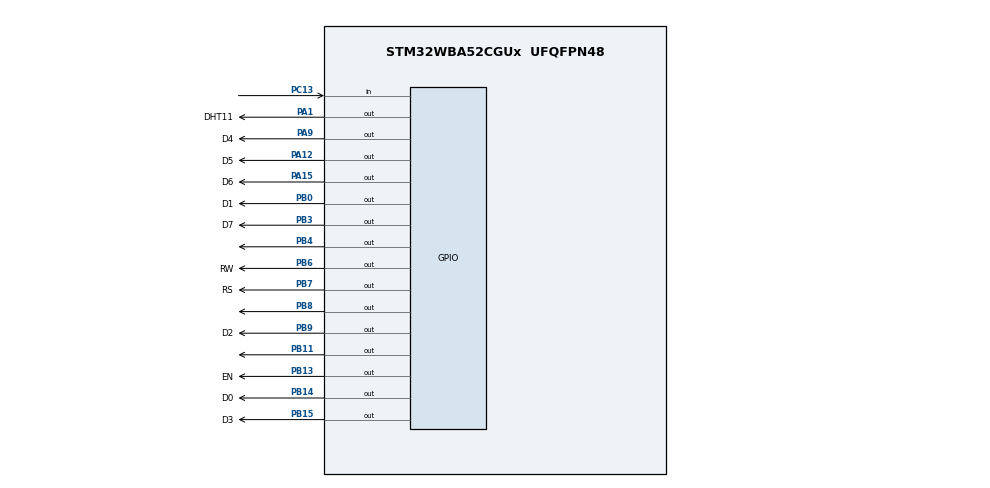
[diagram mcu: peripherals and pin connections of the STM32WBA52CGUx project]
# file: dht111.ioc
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CORTEX_M33_NS.userName=CORTEX_M33
Mcu.Family=STM32WBA
Mcu.Name=STM32WBA52CGUx
Mcu.Package=UFQFPN48
NUCLEO-WBA52CG.BUTTON=1
NUCLEO-WBA52CG.BUTTON2=1
NUCLEO-WBA52CG.BUTTON3=1
NUCLEO-WBA52CG.LD1=true
NUCLEO-WBA52CG.LD2=true
NUCLEO-WBA52CG.LD3=true
NUCLEO-WBA52CG.VCP=true
NVIC.EXTI13_IRQn=true\:0\:0\:false\:false\:true\:true\:true\:true
NVIC.EXTI6_IRQn=true\:0\:0\:false\:false\:true\:true\:true\:true
NVIC.EXTI7_IRQn=true\:0\:0\:false\:false\:true\:true\:true\:true
NVIC.PriorityGroup=NVIC_PRIORITYGROUP_4
OSC_IN.GPIO_Label=RCC_OSC_IN
OSC_IN.Mode=HSE-External-Oscillator
OSC_IN.Signal=RCC_OSC_IN
OSC_OUT.GPIO_Label=RCC_OSC_OUT
OSC_OUT.Mode=HSE-External-Oscillator
OSC_OUT.Signal=RCC_OSC_OUT
PA1.GPIO_Label=DHT11
PA1.Signal=GPIO_Output
PA12.GPIO_Label=D5
PA12.Signal=GPIO_Output
PA13\ (JTMS/SWDIO).GPIO_Label=DEBUG_JTMS-SWDIO
PA13\ (JTMS/SWDIO).Signal=DEBUG_JTMS-SWDIO
PA14\ (JTCK/SWCLK).GPIO_Label=DEBUG_JTCK-SWCLK
PA14\ (JTCK/SWCLK).Signal=DEBUG_JTCK-SWCLK
PA15\ (JTDI).GPIO_Label=D6
PA15\ (JTDI).Signal=GPIO_Output
PA8.Signal=USART1_RX
PA9.GPIO_Label=D4
PA9.Signal=GPIO_Output
PB0.GPIO_Label=D1
PB0.Signal=GPIO_Output
PB11.Signal=GPIO_Output
PB12.Signal=USART1_TX
PB13.GPIO_Label=EN
PB13.Signal=GPIO_Output
PB14.GPIO_Label=D0
PB14.Signal=GPIO_Output
PB15.GPIO_Label=D3
PB15.Signal=GPIO_Output
PB3\ (JTDO/TRACESWO).GPIO_Label=D7
PB3\ (JTDO/TRACESWO).Signal=GPIO_Output
PB4\ (NJTRST).Signal=GPIO_Output
PB6.GPIO_Label=RW
PB6.Signal=GPIO_Output
PB7.GPIO_Label=RS
PB7.Signal=GPIO_Output
PB8.Signal=GPIO_Output
PB9.GPIO_Label=D2
PB9.Signal=GPIO_Output
PC13.Signal=GPIO_Input
PC14-OSC32_IN.GPIO_Label=RCC_OSC32_IN
PC14-OSC32_IN.Signal=RCC_OSC32_IN
PC15-OSC32_OUT.GPIO_Label=RCC_OSC32_OUT
PC15-OSC32_OUT.Signal=RCC_OSC32_OUT
ProjectManager.HeapSize=0x200
ProjectManager.StackSize=0x400
ProjectManager.TargetToolchain=STM32CubeIDE
RCC.ADCFreq_Value=50000000
RCC.AHB5CLKDivider=DIV2
RCC.AHBFreq_Value=50000000
RCC.APB1Freq_Value=50000000
RCC.APB1TimFreq_Value=50000000
RCC.APB2Freq_Value=50000000
RCC.APB2TimFreq_Value=50000000
RCC.CortexFreq_Value=6250000
RCC.FLatency=FLASH_LATENCY_1
RCC.HCLKFreq_Value=50000000
RCC.HSE_VALUE=32000000
RCC.HSI_VALUE=16000000
RCC.LSE_VALUE=32768
RCC.PLL1R=3
RCC.PLLFRACN=3072
RCC.PLLM=2
RCC.PLLN=9
RCC.PLLSourceVirtual=RCC_PLLSOURCE_HSE
RCC.SYSCLKFreq_VALUE=50000000
RCC.SYSCLKSourceVirtual=RCC_SYSCLKSOURCE_PLLCLK
RCC.VCOOutputFreq_Value=150000000
TIM1.Prescaler=50-1
VP_CORTEX_M33_NS_VS_Hclk.Mode=Hclk_Mode
VP_ICACHE_VS_ICACHE.Mode=DirectMappedCache
VP_MEMORYMAP_VS_MEMORYMAP.Mode=CurAppReg
VP_NUCLEO-WBA52CG_VS_BSP_COMMON.Mode=COMMON
VP_PWR_VS_SECSignals.Mode=Security/Privilege
VP_TIM1_VS_ClockSourceINT.Mode=Internal
board=NUCLEO-WBA52CG

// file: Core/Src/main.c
/* USER CODE BEGIN Header */
/* USER CODE END Header */
#include "main.h"
#include"LCD.h"

COM_InitTypeDef BspCOMInit;

TIM_HandleTypeDef htim1;

void SystemClock_Config(void);
static void MX_GPIO_Init(void);
static void MX_ICACHE_Init(void);
static void MX_TIM1_Init(void);

/* USER CODE BEGIN 0 */
void delay (uint16_t time)
{
	/* change your code here for the delay in microseconds */
	__HAL_TIM_SET_COUNTER(&htim1, 0);
	while ((__HAL_TIM_GET_COUNTER(&htim1))<time);
}

void Display_Temp (float Temp)
{
	char str[20] = {0};
	LCD_cmd(0x80);

	sprintf (str, "TEMP:- %.2f ", Temp);
	LCD_Print(str);
	LCD_data('C');
}

void Display_Rh (float Rh)
{
	char str[20] = {0};
	LCD_cmd(0xc0);
	sprintf (str, "RH:- %.2f ", Rh);
	LCD_Print(str);
	LCD_data('H');
}

uint8_t Rh_byte1, Rh_byte2, Temp_byte1, Temp_byte2;
uint16_t SUM, RH, TEMP;

float Temperature = 0;
float Humidity = 0;
uint8_t Presence = 0;

void Set_Pin_Output (GPIO_TypeDef *GPIOx, uint16_t GPIO_Pin)
{
	GPIO_InitTypeDef GPIO_InitStruct = {0};
	GPIO_InitStruct.Pin = GPIO_Pin;
	GPIO_InitStruct.Mode = GPIO_MODE_OUTPUT_PP;
	GPIO_InitStruct.Speed = GPIO_SPEED_FREQ_LOW;
	HAL_GPIO_Init(GPIOx, &GPIO_InitStruct);
}

void Set_Pin_Input (GPIO_TypeDef *GPIOx, uint16_t GPIO_Pin)
{
	GPIO_InitTypeDef GPIO_InitStruct = {0};
	GPIO_InitStruct.Pin = GPIO_Pin;
	GPIO_InitStruct.Mode = GPIO_MODE_INPUT;
	GPIO_InitStruct.Pull = GPIO_PULLUP;
	HAL_GPIO_Init(GPIOx, &GPIO_InitStruct);
}

/*********************************** DHT11 FUNCTIONS ********************************************/

#define DHT11_PORT GPIOA
#define DHT11_PIN GPIO_PIN_1

void DHT11_Start (void)
{
	Set_Pin_Output (DHT11_PORT, DHT11_PIN);  // set the pin as output
	HAL_GPIO_WritePin (DHT11_PORT, DHT11_PIN, 0);   // pull the pin low
	delay (18000);   // wait for 18ms
    HAL_GPIO_WritePin (DHT11_PORT, DHT11_PIN, 1);   // pull the pin high
	delay (20);   // wait for 20us
	Set_Pin_Input(DHT11_PORT, DHT11_PIN);    // set as input
}

uint8_t DHT11_Check_Response (void)
{
	uint8_t Response = 0;
	delay (40);
	if (!(HAL_GPIO_ReadPin (DHT11_PORT, DHT11_PIN)))
	{
		delay (80);
		if ((HAL_GPIO_ReadPin (DHT11_PORT, DHT11_PIN))) Response = 1;
		else Response = -1; // 255
	}
	while ((HAL_GPIO_ReadPin (DHT11_PORT, DHT11_PIN)));   // wait for the pin to go low

	return Response;
}

uint8_t DHT11_Read (void)
{
	uint8_t i,j;
	for (j=0;j<8;j++)
	{
		while (!(HAL_GPIO_ReadPin (DHT11_PORT, DHT11_PIN)));   // wait for the pin to go high
		delay (40);   // wait for 40 us
		if (!(HAL_GPIO_ReadPin (DHT11_PORT, DHT11_PIN)))   // if the pin is low
		{
			i&= ~(1<<(7-j));   // write 0
		}
		else i|= (1<<(7-j));  // if the pin is high, write 1
		while ((HAL_GPIO_ReadPin (DHT11_PORT, DHT11_PIN)));  // wait for the pin to go low
	}
	return i;
}
/* USER CODE END 0 */

int main(void)
{

  /* MCU Configuration--------------------------------------------------------*/

  /* Reset of all peripherals, Initializes the Flash interface and the Systick. */
  HAL_Init();

  /* Configure the system clock */
  SystemClock_Config();

  /* Initialize all configured peripherals */
  MX_GPIO_Init();
  MX_ICACHE_Init();
  MX_TIM1_Init();
  LCD_init();
  /* USER CODE BEGIN 2 */
    LCD_Print("INITIALISING>>>>");
    HAL_Delay(2000);
    LCD_cmd(0x01);

    /* USER CODE END 2 */

    /* Infinite loop */
     while (1)
     {

       /* USER CODE BEGIN 3 */

   	  Display_Temp(Temperature);
   	  Display_Rh(Humidity);

   	  DHT11_Start();
   	  Presence = DHT11_Check_Response();
   	  Rh_byte1 = DHT11_Read ();
   	  Rh_byte2 = DHT11_Read ();
   	  Temp_byte1 = DHT11_Read ();
   	  Temp_byte2 = DHT11_Read ();
   	  SUM = DHT11_Read();

   	  TEMP = Temp_byte1;
   	  RH = Rh_byte1;

   	  Temperature = (float) TEMP;
   	  Humidity = (float) RH;

   	  HAL_Delay(1000);

     }

  /* USER CODE END 2 */
  /* Initialize COM1 port (115200, 8 bits (7-bit data + 1 stop bit), no parity */
  BspCOMInit.BaudRate   = 115200;
  BspCOMInit.WordLength = COM_WORDLENGTH_8B;
  BspCOMInit.StopBits   = COM_STOPBITS_1;
  BspCOMInit.Parity     = COM_PARITY_NONE;
  BspCOMInit.HwFlowCtl  = COM_HWCONTROL_NONE;
  if (BSP_COM_Init(COM1, &BspCOMInit) != BSP_ERROR_NONE)
  {
    Error_Handler();
  }

  /* Infinite loop */
  /* USER CODE BEGIN WHILE */
    /* USER CODE END WHILE */

    /* USER CODE BEGIN 3 */
  /* USER CODE END 3 */
}

void SystemClock_Config(void)
{
  RCC_OscInitTypeDef RCC_OscInitStruct = {0};
  RCC_ClkInitTypeDef RCC_ClkInitStruct = {0};

  /** Configure the main internal regulator output voltage
  */
  if (HAL_PWREx_ControlVoltageScaling(PWR_REGULATOR_VOLTAGE_SCALE1) != HAL_OK)
  {
    Error_Handler();
  }

  /** Initializes the CPU, AHB and APB busses clocks
  */
  RCC_OscInitStruct.OscillatorType = RCC_OSCILLATORTYPE_HSE;
  RCC_OscInitStruct.HSEState = RCC_HSE_ON;
  RCC_OscInitStruct.HSEDiv = RCC_HSE_DIV1;
  RCC_OscInitStruct.PLL1.PLLState = RCC_PLL_ON;
  RCC_OscInitStruct.PLL1.PLLSource = RCC_PLLSOURCE_HSE;
  RCC_OscInitStruct.PLL1.PLLM = 2;
  RCC_OscInitStruct.PLL1.PLLN = 9;
  RCC_OscInitStruct.PLL1.PLLP = 2;
  RCC_OscInitStruct.PLL1.PLLQ = 2;
  RCC_OscInitStruct.PLL1.PLLR = 3;
  RCC_OscInitStruct.PLL1.PLLFractional = 3072;
  if (HAL_RCC_OscConfig(&RCC_OscInitStruct) != HAL_OK)
  {
    Error_Handler();
  }

  /** Initializes the CPU, AHB and APB busses clocks
  */
  RCC_ClkInitStruct.ClockType = RCC_CLOCKTYPE_HCLK|RCC_CLOCKTYPE_SYSCLK
                              |RCC_CLOCKTYPE_PCLK1|RCC_CLOCKTYPE_PCLK2
                              |RCC_CLOCKTYPE_PCLK7|RCC_CLOCKTYPE_HCLK5;
  RCC_ClkInitStruct.SYSCLKSource = RCC_SYSCLKSOURCE_PLLCLK;
  RCC_ClkInitStruct.AHBCLKDivider = RCC_SYSCLK_DIV1;
  RCC_ClkInitStruct.APB1CLKDivider = RCC_HCLK_DIV1;
  RCC_ClkInitStruct.APB2CLKDivider = RCC_HCLK_DIV1;
  RCC_ClkInitStruct.APB7CLKDivider = RCC_HCLK_DIV1;
  RCC_ClkInitStruct.AHB5_PLL1_CLKDivider = RCC_SYSCLK_PLL1_DIV2;
  RCC_ClkInitStruct.AHB5_HSEHSI_CLKDivider = RCC_SYSCLK_HSEHSI_DIV1;

  if (HAL_RCC_ClockConfig(&RCC_ClkInitStruct, FLASH_LATENCY_1) != HAL_OK)
  {
    Error_Handler();
  }
}

static void MX_ICACHE_Init(void)
{

  /** Enable instruction cache in 1-way (direct mapped cache)
  */
  if (HAL_ICACHE_ConfigAssociativityMode(ICACHE_1WAY) != HAL_OK)
  {
    Error_Handler();
  }
  if (HAL_ICACHE_Enable() != HAL_OK)
  {
    Error_Handler();
  }

}

static void MX_TIM1_Init(void)
{

  TIM_ClockConfigTypeDef sClockSourceConfig = {0};
  TIM_MasterConfigTypeDef sMasterConfig = {0};

  htim1.Instance = TIM1;
  htim1.Init.Prescaler = 50-1;
  htim1.Init.CounterMode = TIM_COUNTERMODE_UP;
  htim1.Init.Period = 65535;
  htim1.Init.ClockDivision = TIM_CLOCKDIVISION_DIV1;
  htim1.Init.RepetitionCounter = 0;
  htim1.Init.AutoReloadPreload = TIM_AUTORELOAD_PRELOAD_DISABLE;
  if (HAL_TIM_Base_Init(&htim1) != HAL_OK)
  {
    Error_Handler();
  }
  sClockSourceConfig.ClockSource = TIM_CLOCKSOURCE_INTERNAL;
  if (HAL_TIM_ConfigClockSource(&htim1, &sClockSourceConfig) != HAL_OK)
  {
    Error_Handler();
  }
  sMasterConfig.MasterOutputTrigger = TIM_TRGO_RESET;
  sMasterConfig.MasterOutputTrigger2 = TIM_TRGO2_RESET;
  sMasterConfig.MasterSlaveMode = TIM_MASTERSLAVEMODE_DISABLE;
  if (HAL_TIMEx_MasterConfigSynchronization(&htim1, &sMasterConfig) != HAL_OK)
  {
    Error_Handler();
  }

}

static void MX_GPIO_Init(void)
{
  GPIO_InitTypeDef GPIO_InitStruct = {0};

  /* GPIO Ports Clock Enable */
  __HAL_RCC_GPIOA_CLK_ENABLE();
  __HAL_RCC_GPIOB_CLK_ENABLE();
  __HAL_RCC_GPIOC_CLK_ENABLE();

  /*Configure GPIO pin Output Level */
  HAL_GPIO_WritePin(GPIOA, DHT11_Pin|D6_Pin|D5_Pin|D4_Pin, GPIO_PIN_RESET);

  /*Configure GPIO pin Output Level */
  HAL_GPIO_WritePin(GPIOB, D2_Pin|RS_Pin|RW_Pin|D7_Pin
                          |D1_Pin|D3_Pin|D0_Pin|EN_Pin, GPIO_PIN_RESET);

  /*Configure GPIO pins : DHT11_Pin D6_Pin D5_Pin D4_Pin */
  GPIO_InitStruct.Pin = DHT11_Pin|D6_Pin|D5_Pin|D4_Pin;
  GPIO_InitStruct.Mode = GPIO_MODE_OUTPUT_PP;
  GPIO_InitStruct.Pull = GPIO_NOPULL;
  GPIO_InitStruct.Speed = GPIO_SPEED_FREQ_LOW;
  HAL_GPIO_Init(GPIOA, &GPIO_InitStruct);

  /*Configure GPIO pins : D2_Pin RS_Pin RW_Pin D7_Pin
                           D1_Pin D3_Pin D0_Pin EN_Pin */
  GPIO_InitStruct.Pin = D2_Pin|RS_Pin|RW_Pin|D7_Pin
                          |D1_Pin|D3_Pin|D0_Pin|EN_Pin;
  GPIO_InitStruct.Mode = GPIO_MODE_OUTPUT_PP;
  GPIO_InitStruct.Pull = GPIO_NOPULL;
  GPIO_InitStruct.Speed = GPIO_SPEED_FREQ_LOW;
  HAL_GPIO_Init(GPIOB, &GPIO_InitStruct);

}

void Error_Handler(void)
{
}
